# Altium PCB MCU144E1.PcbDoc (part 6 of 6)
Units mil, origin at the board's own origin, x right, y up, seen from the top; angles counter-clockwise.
Board outline 2755.9 x 2276.49 mil, 10 copper layers (Top Layer, L02_GND1, L03_SIG1, L04_GND2, L05_SIG2, L06_PWR, L07_GND3, L08_SIG3, L09_GND4, Bottom Layer), stack 60.4 mil thick; 257 components, 312 nets, 1297 pads, 831 vias.

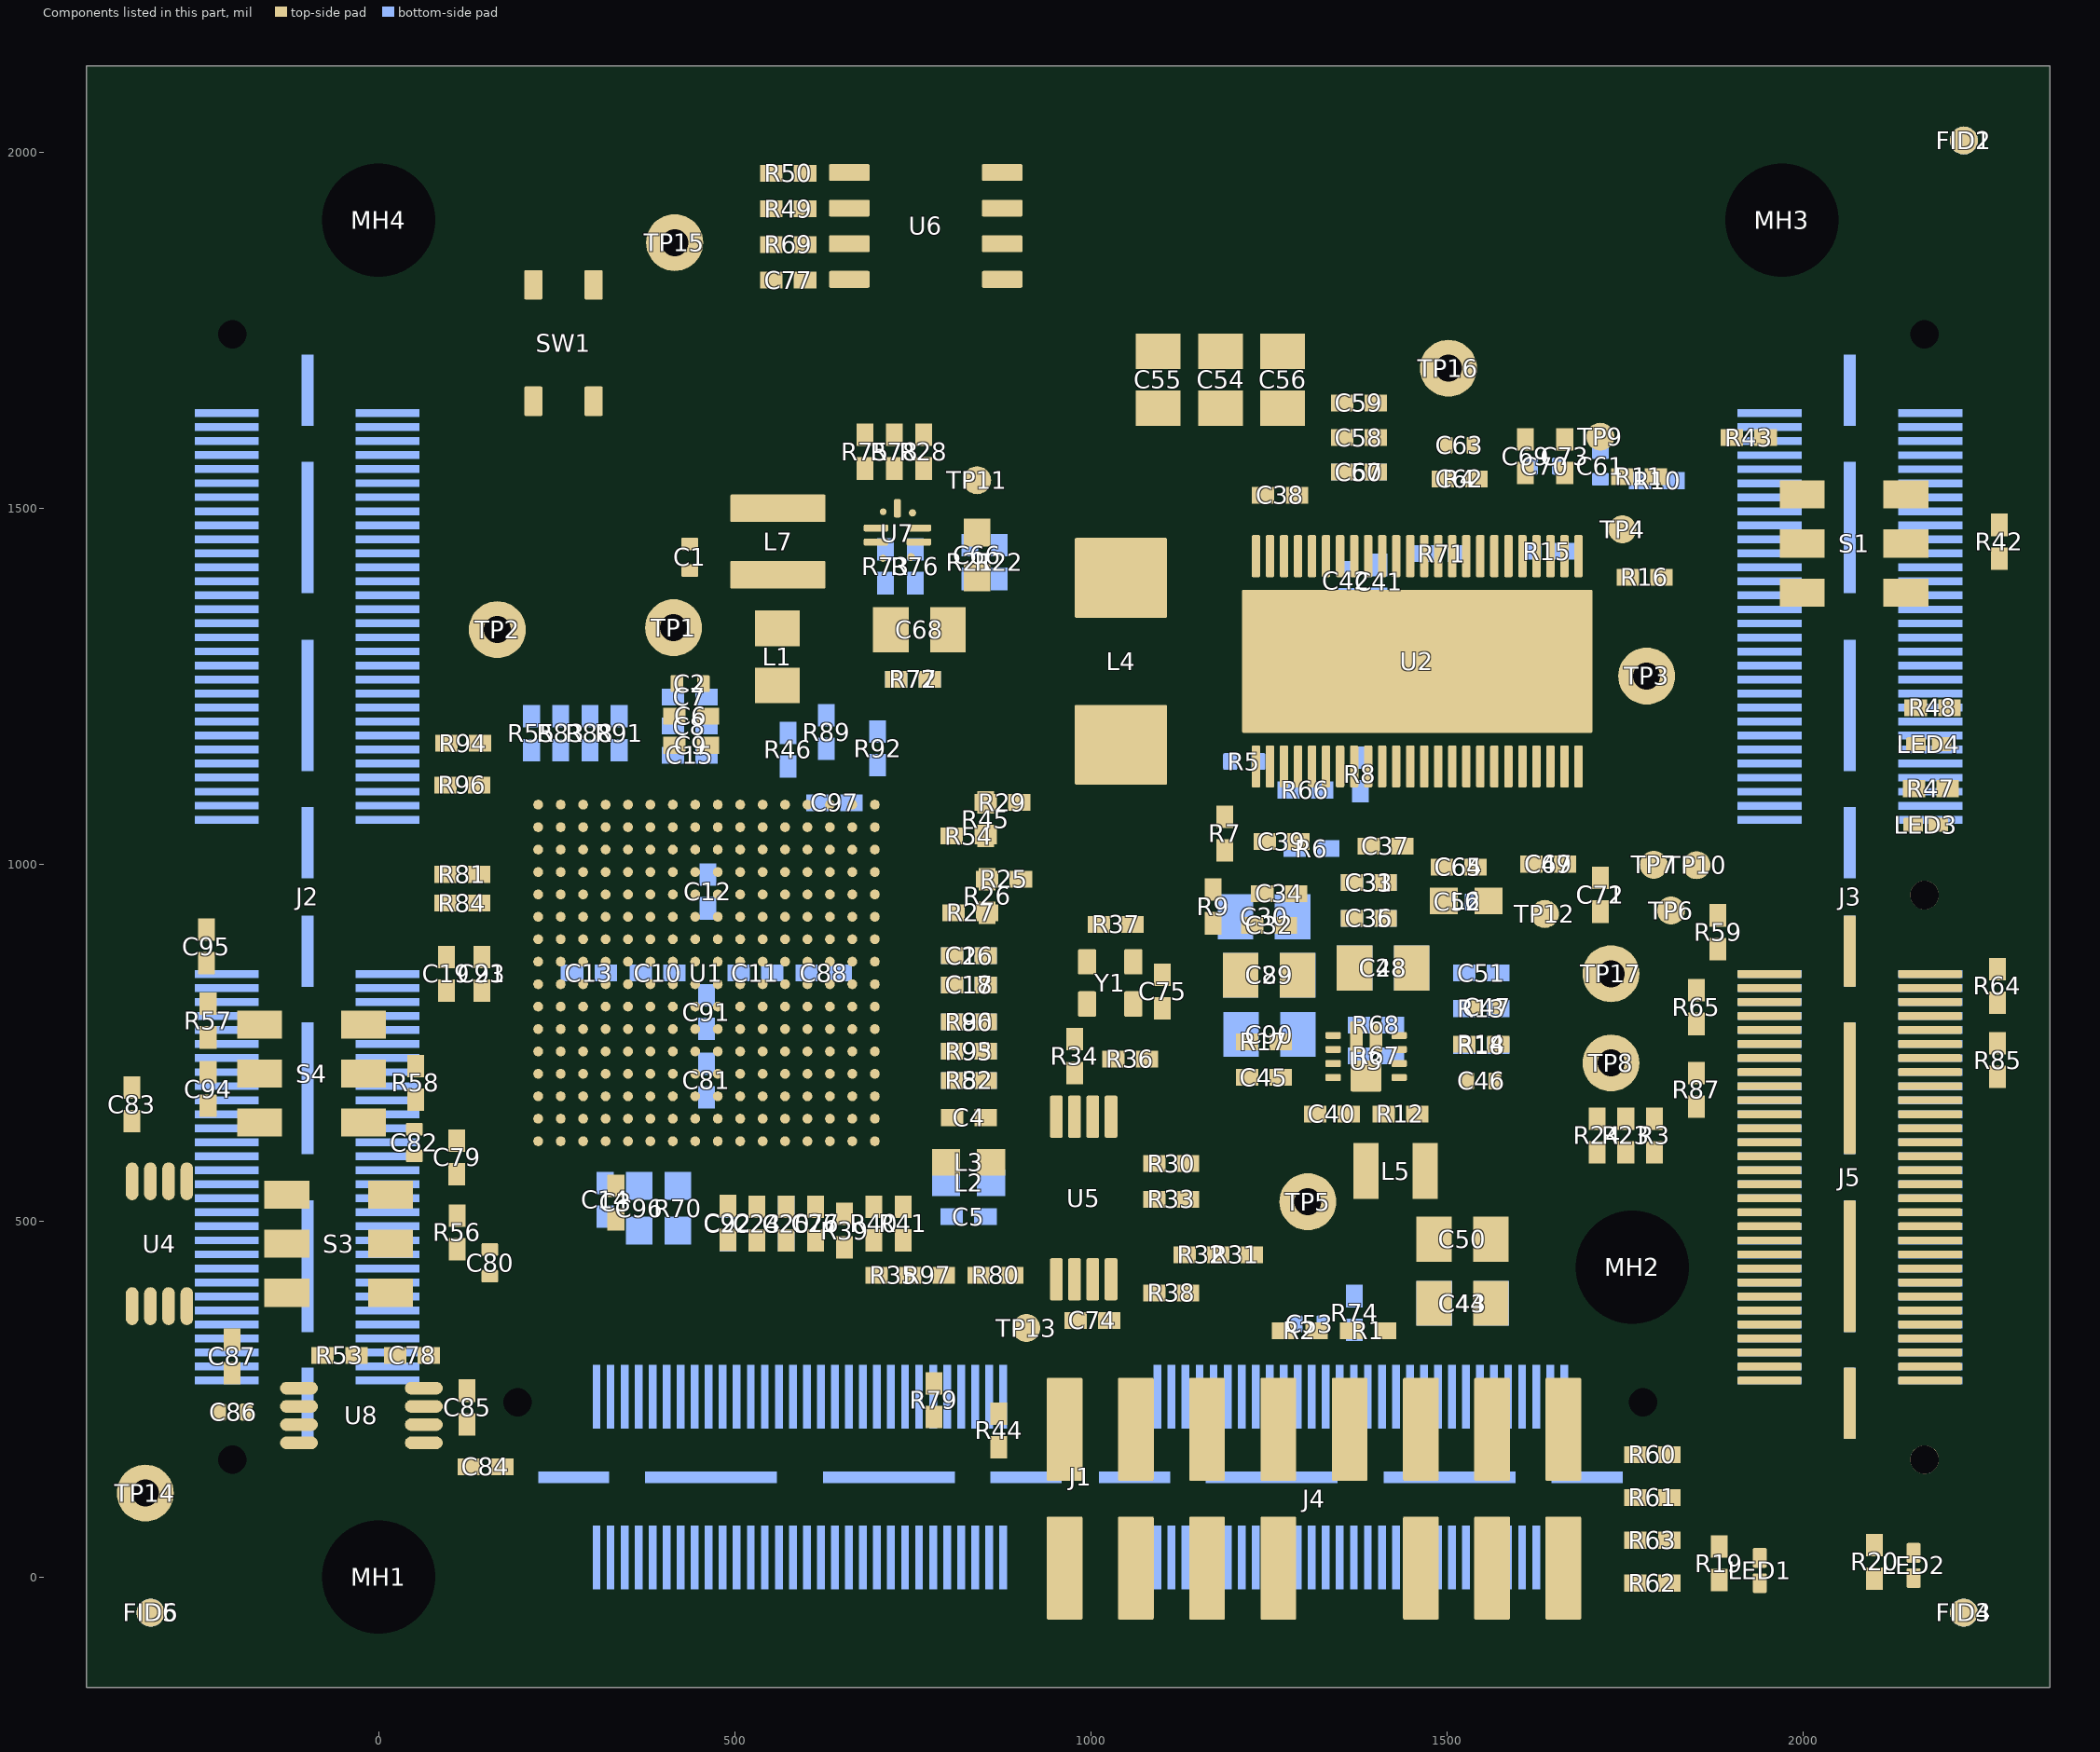
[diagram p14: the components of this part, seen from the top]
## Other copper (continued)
L08_SIG3:
  pour cut-out: 1221.72,1187.13 cw(c1221.72,1199.13) 1209.72,1199.13 cw(c1221.72,1199.13) 1221.72,1211.13 cw(c1221.72,1199.13) 1233.72,1199.13 cw(c1221.72,1199.13)
  pour cut-out: 1646.92,1187.13 cw(c1646.92,1199.13) 1634.92,1199.13 cw(c1646.92,1199.13) 1646.92,1211.13 cw(c1646.92,1199.13) 1658.92,1199.13 cw(c1646.92,1199.13)
  pour cut-out: 1694.16,1187.13 cw(c1694.16,1199.13) 1682.16,1199.13 cw(c1694.16,1199.13) 1694.16,1211.13 cw(c1694.16,1199.13) 1706.16,1199.13 cw(c1694.16,1199.13)
  pour cut-out: 1694.16,1230.43 cw(c1694.16,1242.43) 1682.16,1242.43 cw(c1694.16,1242.43) 1694.16,1254.43 cw(c1694.16,1242.43) 1706.16,1242.43 cw(c1694.16,1242.43)
  pour cut-out: 1694.16,1317.05 cw(c1694.16,1329.05) 1682.16,1329.05 cw(c1694.16,1329.05) 1694.16,1341.05 cw(c1694.16,1329.05) 1706.16,1329.05 cw(c1694.16,1329.05)
  pour cut-out: 1694.16,1360.35 cw(c1694.16,1372.35) 1682.16,1372.35 cw(c1694.16,1372.35) 1694.16,1384.35 cw(c1694.16,1372.35) 1706.16,1372.35 cw(c1694.16,1372.35)
  pour cut-out: 1646.92,1360.35 cw(c1646.92,1372.35) 1634.92,1372.35 cw(c1646.92,1372.35) 1646.92,1384.35 cw(c1646.92,1372.35) 1658.92,1372.35 cw(c1646.92,1372.35)
  pour cut-out: 1599.67,1360.35 cw(c1599.67,1372.35) 1587.67,1372.35 cw(c1599.67,1372.35) 1599.67,1384.35 cw(c1599.67,1372.35) 1611.67,1372.35 cw(c1599.67,1372.35)
  pour cut-out: 1552.43,1360.35 cw(c1552.43,1372.35) 1540.43,1372.35 cw(c1552.43,1372.35) 1552.43,1384.35 cw(c1552.43,1372.35) 1564.43,1372.35 cw(c1552.43,1372.35)
  pour cut-out: 1505.18,1360.35 cw(c1505.18,1372.35) 1493.18,1372.35 cw(c1505.18,1372.35) 1505.18,1384.35 cw(c1505.18,1372.35) 1517.18,1372.35 cw(c1505.18,1372.35)
  pour cut-out: 1457.94,1360.35 cw(c1457.94,1372.35) 1445.94,1372.35 cw(c1457.94,1372.35) 1457.94,1384.35 cw(c1457.94,1372.35) 1469.94,1372.35 cw(c1457.94,1372.35)
  pour cut-out: 1316.21,1360.35 cw(c1316.21,1372.35) 1304.21,1372.35 cw(c1316.21,1372.35) 1316.21,1384.35 cw(c1316.21,1372.35) 1328.21,1372.35 cw(c1316.21,1372.35)
  pour cut-out: 1268.96,1360.35 cw(c1268.96,1372.35) 1256.96,1372.35 cw(c1268.96,1372.35) 1268.96,1384.35 cw(c1268.96,1372.35) 1280.96,1372.35 cw(c1268.96,1372.35)
  pour cut-out: 1221.72,1230.43 cw(c1221.72,1242.43) 1209.72,1242.43 cw(c1221.72,1242.43) 1221.72,1254.43 cw(c1221.72,1242.43) 1233.72,1242.43 cw(c1221.72,1242.43)
  pour cut-out: 1221.72,1273.74 cw(c1221.72,1285.74) 1209.72,1285.74 cw(c1221.72,1285.74) 1221.72,1297.74 cw(c1221.72,1285.74) 1233.72,1285.74 cw(c1221.72,1285.74)
  pour cut-out: 1221.72,1317.05 cw(c1221.72,1329.05) 1209.72,1329.05 cw(c1221.72,1329.05) 1221.72,1341.05 cw(c1221.72,1329.05) 1233.72,1329.05 cw(c1221.72,1329.05)
  pour cut-out: 1221.72,1360.35 cw(c1221.72,1372.35) 1209.72,1372.35 cw(c1221.72,1372.35) 1221.72,1384.35 cw(c1221.72,1372.35) 1233.72,1372.35 cw(c1221.72,1372.35)
  pour cut-out: 951.38,584.38 cw(c951.38,596.38) 939.38,596.38 cw(c951.38,596.38) 951.38,608.38 cw(c951.38,596.38) 963.38,596.38 cw(c951.38,596.38)
  pour cut-out: 180.44,1638.94 cw(c180.44,1650.94) 168.44,1650.94 cw(c180.44,1650.94) 180.44,1662.94 cw(c180.44,1650.94) 192.44,1650.94 cw(c180.44,1650.94)
  pour cut-out: 509.25,1810 cw(c509.25,1822) 497.25,1822 cw(c509.25,1822) 509.25,1834 cw(c509.25,1822) 521.25,1822 cw(c509.25,1822)
  pour cut-out: 509.25,1860 cw(c509.25,1872) 497.25,1872 cw(c509.25,1872) 509.25,1884 cw(c509.25,1872) 521.25,1872 cw(c509.25,1872)
  pour cut-out: 936.95,1860 cw(c936.95,1872) 924.95,1872 cw(c936.95,1872) 936.95,1884 cw(c936.95,1872) 948.95,1872 cw(c936.95,1872)
  pour cut-out: 724,1623.21 cw(c724,1635.21) 712,1635.21 cw(c724,1635.21) 724,1647.21 cw(c724,1635.21) 736,1635.21 cw(c724,1635.21)
  pour cut-out: 765,1623.21 cw(c765,1635.21) 753,1635.21 cw(c765,1635.21) 765,1647.21 cw(c765,1635.21) 777,1635.21 cw(c765,1635.21)
  pour cut-out: 1620.79,1625.88 cw(c1620.79,1637.88) 1608.79,1637.88 cw(c1620.79,1637.88) 1620.79,1649.88 cw(c1620.79,1637.88) 1632.79,1637.88 cw(c1620.79,1637.88)
  pour cut-out: 1571.68,1624.97 cw(c1571.68,1636.97) 1559.68,1636.97 cw(c1571.68,1636.97) 1571.68,1648.97 cw(c1571.68,1636.97) 1583.68,1636.97 cw(c1571.68,1636.97)
  pour cut-out: 1521.26,1624.97 cw(c1521.26,1636.97) 1509.26,1636.97 cw(c1521.26,1636.97) 1521.26,1648.97 cw(c1521.26,1636.97) 1533.26,1636.97 cw(c1521.26,1636.97)
  pour cut-out: 1435.68,1625.82 cw(c1435.68,1637.82) 1423.68,1637.82 cw(c1435.68,1637.82) 1435.68,1649.82 cw(c1435.68,1637.82) 1447.68,1637.82 cw(c1435.68,1637.82)
  pour cut-out: 1936.77,52.55 cw(c1936.77,64.55) 1924.77,64.55 cw(c1936.77,64.55) 1936.77,76.55 cw(c1936.77,64.55) 1948.77,64.55 cw(c1936.77,64.55)
  pour cut-out: 2065,318.61 cw(c2065,330.61) 2053,330.61 cw(c2065,330.61) 2065,342.61 cw(c2065,330.61) 2077,330.61 cw(c2065,330.61)
  pour cut-out: 1169.18,518.38 cw(c1169.18,530.38) 1157.18,530.38 cw(c1169.18,530.38) 1169.18,542.38 cw(c1169.18,530.38) 1181.18,530.38 cw(c1169.18,530.38)
  pour cut-out: 1166,785.5 cw(c1166,797.5) 1154,797.5 cw(c1166,797.5) 1166,809.5 cw(c1166,797.5) 1178,797.5 cw(c1166,797.5)
  pour cut-out: 1593.48,684.52 cw(c1593.48,696.52) 1581.48,696.52 cw(c1593.48,696.52) 1593.48,708.52 cw(c1593.48,696.52) 1605.48,696.52 cw(c1593.48,696.52)
  pour cut-out: 2065,569.43 cw(c2065,581.43) 2053,581.43 cw(c2065,581.43) 2065,593.43 cw(c2065,581.43) 2077,581.43 cw(c2065,581.43)
  pour cut-out: 2065,318.61 cw(c2065,330.61) 2053,330.61 cw(c2065,330.61) 2065,342.61 cw(c2065,330.61) 2077,330.61 cw(c2065,330.61)
  pour cut-out: 2154.81,51.4 cw(c2154.81,63.4) 2142.81,63.4 cw(c2154.81,63.4) 2154.81,75.4 cw(c2154.81,63.4) 2166.81,63.4 cw(c2154.81,63.4)
  pour cut-out: 1506.84,70.74 cw(c1506.84,82.74) 1494.84,82.74 cw(c1506.84,82.74) 1506.84,94.74 cw(c1506.84,82.74) 1518.84,82.74 cw(c1506.84,82.74)
  pour cut-out: 1315,128 cw(c1315,140) 1303,140 cw(c1315,140) 1315,152 cw(c1315,140) 1327,140 cw(c1315,140)
  pour cut-out: 1115,128 cw(c1115,140) 1103,140 cw(c1115,140) 1115,152 cw(c1115,140) 1127,140 cw(c1115,140)
  pour cut-out: 1025.56,315.1 cw(c1025.56,327.1) 1013.56,327.1 cw(c1025.56,327.1) 1025.56,339.1 cw(c1025.56,327.1) 1037.56,327.1 cw(c1025.56,327.1)
  pour cut-out: 815,151 cw(c815,163) 803,163 cw(c815,163) 815,175 cw(c815,163) 827,163 cw(c815,163)
  pour cut-out: 700.81,308.3 cw(c700.81,320.3) 688.81,320.3 cw(c700.81,320.3) 700.81,332.3 cw(c700.81,320.3) 712.81,320.3 cw(c700.81,320.3)
  pour cut-out: -339.37,441.54 cw(c-339.37,453.54) -351.37,453.54 cw(c-339.37,453.54) -339.37,465.54 cw(c-339.37,453.54) -327.37,453.54 cw(c-339.37,453.54)
  pour cut-out: -337.61,501.04 cw(c-337.61,513.04) -349.61,513.04 cw(c-337.61,513.04) -337.61,525.04 cw(c-337.61,513.04) -325.61,513.04 cw(c-337.61,513.04)
  pour cut-out: 99.44,272.6 cw(c99.44,284.6) 87.44,284.6 cw(c99.44,284.6) 99.44,296.6 cw(c99.44,284.6) 111.44,284.6 cw(c99.44,284.6)
  pour cut-out: 8.92,228.11 cw(c8.92,240.11) -3.08,240.11 cw(c8.92,240.11) 8.92,252.11 cw(c8.92,240.11) 20.92,240.11 cw(c8.92,240.11)
  pour cut-out: -76.47,519.83 cw(c-76.47,531.83) -88.47,531.83 cw(c-76.47,531.83) -76.47,543.83 cw(c-76.47,531.83) -64.47,531.83 cw(c-76.47,531.83)
  pour cut-out: -77.37,425.84 cw(c-77.37,437.84) -89.37,437.84 cw(c-77.37,437.84) -77.37,449.84 cw(c-77.37,437.84) -65.37,437.84 cw(c-77.37,437.84)
  pour cut-out: 333.39,458.53 cw(c333.39,470.53) 321.39,470.53 cw(c333.39,470.53) 333.39,482.53 cw(c333.39,470.53) 345.39,470.53 cw(c333.39,470.53)
  pour cut-out: 1446.33,913 cw(c1446.33,925) 1434.33,925 cw(c1446.33,925) 1446.33,937 cw(c1446.33,925) 1458.33,925 cw(c1446.33,925)
  pour cut-out: 1446.33,963 cw(c1446.33,975) 1434.33,975 cw(c1446.33,975) 1446.33,987 cw(c1446.33,975) 1458.33,975 cw(c1446.33,975)
  pour cut-out: 1166,858 cw(c1166,870) 1154,870 cw(c1166,870) 1166,882 cw(c1166,870) 1178,870 cw(c1166,870)
  pour cut-out: 887.7,860.1 cw(c887.7,872.1) 875.7,872.1 cw(c887.7,872.1) 887.7,884.1 cw(c887.7,872.1) 899.7,872.1 cw(c887.7,872.1)
  pour cut-out: 680.73,962.2 cw(c680.73,974.2) 668.73,974.2 cw(c680.73,974.2) 680.73,986.2 cw(c680.73,974.2) 692.73,974.2 cw(c680.73,974.2)
  pour cut-out: 712.23,1088.18 cw(c712.23,1100.18) 700.23,1100.18 cw(c712.23,1100.18) 712.23,1112.18 cw(c712.23,1100.18) 724.23,1100.18 cw(c712.23,1100.18)
  pour cut-out: 428.76,773.22 cw(c428.76,785.22) 416.76,785.22 cw(c428.76,785.22) 428.76,797.22 cw(c428.76,785.22) 440.76,785.22 cw(c428.76,785.22)
  pour cut-out: 428.76,804.72 cw(c428.76,816.72) 416.76,816.72 cw(c428.76,816.72) 428.76,828.72 cw(c428.76,816.72) 440.76,816.72 cw(c428.76,816.72)
  pour cut-out: 428.76,867.71 cw(c428.76,879.71) 416.76,879.71 cw(c428.76,879.71) 428.76,891.71 cw(c428.76,879.71) 440.76,879.71 cw(c428.76,879.71)
  pour cut-out: 397.27,867.71 cw(c397.27,879.71) 385.27,879.71 cw(c397.27,879.71) 397.27,891.71 cw(c397.27,879.71) 409.27,879.71 cw(c397.27,879.71)
  pour cut-out: 208.29,1088.18 cw(c208.29,1100.18) 196.29,1100.18 cw(c208.29,1100.18) 208.29,1112.18 cw(c208.29,1100.18) 220.29,1100.18 cw(c208.29,1100.18)
  pour cut-out: 1075.84,629.06 1075.84,604.16 1149.62,530.38 1169.18,530.38 1188.8,550 1200,550 1100,650
  text ".Layer_Name" at -94.71,-2471.24 h60
L09_GND4:
  text ".Layer_Name" at -77.19,-2506.29 h60
L05_SIG2:
  pour cut-out: 1410.7,1273.74 cw(c1410.7,1285.74) 1398.7,1285.74 cw(c1410.7,1285.74) 1410.7,1297.74 cw(c1410.7,1285.74) 1422.7,1285.74 cw(c1410.7,1285.74)
  pour cut-out: 1457.94,1230.43 cw(c1457.94,1242.43) 1445.94,1242.43 cw(c1457.94,1242.43) 1457.94,1254.43 cw(c1457.94,1242.43) 1469.94,1242.43 cw(c1457.94,1242.43)
  pour cut-out: 1410.7,1187.13 cw(c1410.7,1199.13) 1398.7,1199.13 cw(c1410.7,1199.13) 1410.7,1211.13 cw(c1410.7,1199.13) 1422.7,1199.13 cw(c1410.7,1199.13)
  pour cut-out: 1363.45,1230.43 cw(c1363.45,1242.43) 1351.45,1242.43 cw(c1363.45,1242.43) 1363.45,1254.43 cw(c1363.45,1242.43) 1375.45,1242.43 cw(c1363.45,1242.43)
  pour cut-out: 1457.94,1187.13 cw(c1457.94,1199.13) 1445.94,1199.13 cw(c1457.94,1199.13) 1457.94,1211.13 cw(c1457.94,1199.13) 1469.94,1199.13 cw(c1457.94,1199.13)
  pour cut-out: 1410.7,1230.43 cw(c1410.7,1242.43) 1398.7,1242.43 cw(c1410.7,1242.43) 1410.7,1254.43 cw(c1410.7,1242.43) 1422.7,1242.43 cw(c1410.7,1242.43)
  pour cut-out: 1363.45,1273.74 cw(c1363.45,1285.74) 1351.45,1285.74 cw(c1363.45,1285.74) 1363.45,1297.74 cw(c1363.45,1285.74) 1375.45,1285.74 cw(c1363.45,1285.74)
  pour cut-out: 1316.21,1317.05 cw(c1316.21,1329.05) 1304.21,1329.05 cw(c1316.21,1329.05) 1316.21,1341.05 cw(c1316.21,1329.05) 1328.21,1329.05 cw(c1316.21,1329.05)
  pour cut-out: 1363.45,1317.05 cw(c1363.45,1329.05) 1351.45,1329.05 cw(c1363.45,1329.05) 1363.45,1341.05 cw(c1363.45,1329.05) 1375.45,1329.05 cw(c1363.45,1329.05)
  pour cut-out: 1316.21,1360.35 cw(c1316.21,1372.35) 1304.21,1372.35 cw(c1316.21,1372.35) 1316.21,1384.35 cw(c1316.21,1372.35) 1328.21,1372.35 cw(c1316.21,1372.35)
  pour cut-out: 1268.96,1273.74 cw(c1268.96,1285.74) 1256.96,1285.74 cw(c1268.96,1285.74) 1268.96,1297.74 cw(c1268.96,1285.74) 1280.96,1285.74 cw(c1268.96,1285.74)
  pour cut-out: 1268.96,1360.35 cw(c1268.96,1372.35) 1256.96,1372.35 cw(c1268.96,1372.35) 1268.96,1384.35 cw(c1268.96,1372.35) 1280.96,1372.35 cw(c1268.96,1372.35)
  pour cut-out: 1268.96,1317.05 cw(c1268.96,1329.05) 1256.96,1329.05 cw(c1268.96,1329.05) 1268.96,1341.05 cw(c1268.96,1329.05) 1280.96,1329.05 cw(c1268.96,1329.05)
  pour cut-out: 1221.72,1187.13 cw(c1221.72,1199.13) 1209.72,1199.13 cw(c1221.72,1199.13) 1221.72,1211.13 cw(c1221.72,1199.13) 1233.72,1199.13 cw(c1221.72,1199.13)
  pour cut-out: 1221.72,1230.43 cw(c1221.72,1242.43) 1209.72,1242.43 cw(c1221.72,1242.43) 1221.72,1254.43 cw(c1221.72,1242.43) 1233.72,1242.43 cw(c1221.72,1242.43)
  pour cut-out: 1166,785.5 cw(c1166,797.5) 1154,797.5 cw(c1166,797.5) 1166,809.5 cw(c1166,797.5) 1178,797.5 cw(c1166,797.5)
  pour cut-out: 1011.15,926.85 cw(c1011.15,938.85) 999.15,938.85 cw(c1011.15,938.85) 1011.15,950.85 cw(c1011.15,938.85) 1023.15,938.85 cw(c1011.15,938.85)
  pour cut-out: 1534.05,1008.95 cw(c1534.05,1020.95) 1522.05,1020.95 cw(c1534.05,1020.95) 1534.05,1032.95 cw(c1534.05,1020.95) 1546.05,1020.95 cw(c1534.05,1020.95)
  pour cut-out: 1435.59,1659.08 cw(c1435.59,1671.08) 1423.59,1671.08 cw(c1435.59,1671.08) 1435.59,1683.08 cw(c1435.59,1671.08) 1447.59,1671.08 cw(c1435.59,1671.08)
  pour cut-out: 1620.79,1625.88 cw(c1620.79,1637.88) 1608.79,1637.88 cw(c1620.79,1637.88) 1620.79,1649.88 cw(c1620.79,1637.88) 1632.79,1637.88 cw(c1620.79,1637.88)
  pour cut-out: 1571.68,1624.97 cw(c1571.68,1636.97) 1559.68,1636.97 cw(c1571.68,1636.97) 1571.68,1648.97 cw(c1571.68,1636.97) 1583.68,1636.97 cw(c1571.68,1636.97)
  pour cut-out: 1521.26,1624.97 cw(c1521.26,1636.97) 1509.26,1636.97 cw(c1521.26,1636.97) 1521.26,1648.97 cw(c1521.26,1636.97) 1533.26,1636.97 cw(c1521.26,1636.97)
  pour cut-out: 1435.68,1625.82 cw(c1435.68,1637.82) 1423.68,1637.82 cw(c1435.68,1637.82) 1435.68,1649.82 cw(c1435.68,1637.82) 1447.68,1637.82 cw(c1435.68,1637.82)
  pour cut-out: 778.23,1383.49 cw(c778.23,1395.49) 766.23,1395.49 cw(c778.23,1395.49) 778.23,1407.49 cw(c778.23,1395.49) 790.23,1395.49 cw(c778.23,1395.49)
  pour cut-out: 712.23,1088.18 cw(c712.23,1100.18) 700.23,1100.18 cw(c712.23,1100.18) 712.23,1112.18 cw(c712.23,1100.18) 724.23,1100.18 cw(c712.23,1100.18)
  pour cut-out: 554.75,867.71 cw(c554.75,879.71) 542.75,879.71 cw(c554.75,879.71) 554.75,891.71 cw(c554.75,879.71) 566.75,879.71 cw(c554.75,879.71)
  text ".Layer_Name" at -129.75,-2497.53 h60
L06_PWR:
  text ".Layer_Name" at -94.71,-2506.29 h60
Bottom Layer:
  region net GND: 371.29,1276.71 371.29,1265.71 399.55,1237.45 399.55,1155.7 427.44,1155.7 427.44,1248.36 407.4,1268.4 391.66,1268.4 380.35,1279.71 374.29,1279.71
  region net VDDIO_3V3: 423.53,759.93 438.91,759.93 448.45,769.47 448.45,785.22 472.07,785.22 472.07,769.47 482.77,758.77 528.64,758.77 532.13,755.28 532.13,736.44 537.57,731 559,731 565,725 565,716 562,713 519,713 514.36,717.64 514.36,728.47 503.12,739.71 475.32,739.71 472.07,736.46 472.07,704.97 448.45,704.97 448.45,736.46 438.81,746.1 423.6,746.1
  region net GND: 429.47,775.44 433.26,779.22 433.26,789.71 444.51,800.97 475.98,800.97 487.51,789.43 487.51,784.38 496.46,775.44 557.24,775.44 566.07,784.27 565.03,785.31 565.03,822.66 562.22,825.47 523.72,825.47 520.88,828.31 520.88,860.02 531.44,870.58 556.37,870.58 557.85,872.06 557.85,939.59 548.55,948.89 403.54,948.89 399.63,945.03 399.63,836.4 409.55,836.4 417.53,828.42 417.53,798.14 415.01,795.62 393.88,795.62 388.2,789.94 388.2,748.63 392.93,743.9 403.97,743.9 409.02,748.95 409.02,771.34 413.11,775.44
  region net VDD_1V25: 501.62,983.93 501.62,983.75 503.04,982.32 503.04,966.75 499.74,963.45 420.77,963.45 417.48,966.75 417.48,982.32 421.84,986.69 432.7,986.69 444.51,998.5 444.51,1256.39 413.9,1287 395.12,1287 364.42,1317.7 364.42,1348.83 388.36,1372.77 432.23,1372.77 510,1295 510,1144.96 478.35,1113.31 478.35,996.16 487.82,986.69 498.85,986.69
  region net GND: 1528.65,1030 1524.79,1026.14 1524.79,930.21 1530,925 1555,925 1560,930 1560,1025 1555,1030
  region net GND: 1455,1005 1450,1010 1405,1010 1397.87,1002.87 1397.87,913.63 1425,886.5 1425,823.5 1430.06,818.44 1522.32,818.44 1540,836.12 1540,859.74 1519.74,880 1481.5,880 1455,906.5
  region net GND: 1154.51,915 1145,905.49 1145,715 1155,705 1222,705 1236.5,719.5 1236.5,963.5 1230,970 1166.01,970 1154.51,958.5
  region net 5V0_LDO2: 1508.25,1008.81 1478.36,1008.81 1475,1005.45 1475,908.83 1487.47,896.36 1506.36,896.36 1508.25,898.25
  region net 5V0_IN: 1240,520 1310,450 1360,450 1419.45,390.55 1419.45,367.62 1481.57,305.5 1481.57,208.19 1512.25,208.19 1512.25,534.25 1531.48,553.48 1667.22,553.48 1690.18,576.44 1792.08,576.44 1797.51,571 1825.72,571 1831.62,576.9 1831.62,590.38 1822,600 1769,600 1747,622 1499,622 1446.35,674.65 1348.35,674.65 1259.94,674.65 1255.38,670.1 1255.38,640.38 1240,625
  region net 3V3_OUT: 836.04,656.39 836.51,656.86 894.58,656.86 905,646.44 905,500 895,490 840.21,490 836.04,494.17
  region net +12V0: 1318.73,712.95 1322.89,717.11 1322.89,792.81 1332.26,802.18 1353.86,802.18 1359.23,796.81 1391.81,796.81 1395,800 1395,886.5 1382.13,899.37 1382.13,1017.87 1365,1035 1364.46,1034.46 1317.44,1034.46 1313.92,1030.94 1313.92,983.92 1300,970 1265,970 1257.17,962.17 1257.17,719.73 1263.96,712.95
  text ".Layer_Name" at -234.88,-2497.53 h60

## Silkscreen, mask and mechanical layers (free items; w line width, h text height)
Top Overlay:
  region: -223.23,1690 -223.23,1495 -125,1495 -125,1690
  lines w6: -162.58,360.87 -162.58,198.61 -162.58,191.75 -152.4,181.57 ; -95.19,825.63 -95.19,945 -95.19,1311.08 -35.63,1370.64 -35.63,1356.89 -49.56,1370.81 -35.46,1370.81 ; -25.03,825.28 -24.69,825.63 ; 150.03,582 142.03,590 ; 150.03,598 142.03,590 ; 176.2,15.49 176.2,43.8 190,30 176.2,16.2 ; 176.2,29.64 114.07,29.64 24,119.71 -152.41,119.71 -152.41,181.56 ; 220,545 190,545 185,550 185,575 170,590 142.03,590 ; 790,1505 805,1505 805,1575 ; 1101,500 1183,500 1183,570 ; 1325,980 1325,899 ; 1333,907 1325,899 ; 1334,907 1317,907 1325,899 ; 1429.03,1692.22 1429.03,1797.22 ; 1450,990 1450,915 1450,908.53 1489.47,908.53 1494,904 ; 1710.51,-67.52 1741.19,-67.52 1742.81,-67.52 1754.95,-79.66 ; 1719,1178 1719,1097 ; -152.41,181.56 -152.4,181.57 ; -152.4,181.57 -152.4,181.57 ; 805,1575 815,1565 795,1565 805,1575 ; 1429.03,1797.22 1439.03,1787.22 1419.03,1787.22 1429.03,1797.22 ; 1719,1097 1727,1105 1728,1105 1711,1105 1719,1097 ; 91.03,1430.17 263.45,1430.17 263.45,1566.23 91.03,1566.23 91.03,1430.17 ; 371.95,7.17 371.95,143.24 544.37,143.24 544.37,7.17 371.95,7.17
  lines w7: 385,380 385,413.1 391.9,420 655,420 ; 394.37,422.47 394.37,474.37 420,500 445,500 ; 430,485 445,500 ; 430,515 445,500 ; 827.53,1108.08 831.4,1111.96 ; 829.92,1000.44 833.8,1004.32 ; 872.4,1015.96 875.85,1019.4 ; 874.8,908.32 878.67,912.2 ; 1755,915 1755,1030 1760,1035
  text "XRSn" at 350,1985 h55
  text "F29H85X-SOM-EVM" at 985,1835 h90
  text "3V3" at 1465,1750 h55
  text "MCU RESET" at 375,1630 h45
  text "3V0" at -10.05,1623.88 h55
  text "Ext" at 215,1585 h55
  text "VREF" at -20,1580 h55
  text "6V0" at 880,1570 h55
  text "BOOT" at 2010.53,1569.57 h55
  text "0" at 2185.68,1556.86 h25
  text "-" at -165,1450 h60 r90
  text "Ext" at 15,1450 h55 r90
  text "CDE" at 365,1445 h55 r90
  text "VREF" at 64.69,1427.92 h55 r90
  text "VREFHI" at 320.71,1397.79 h55 r90
  text "Int" at 216.58,1376.42 h55
  text "J1.83" at -25,1375 h55
  text "GPIO72" at 2220,1375 h50 r90
  text "GPIO84" at 1955,1370 h50 r90
  text "1" at 2175,1320 h25
  text "3V3" at 40,1240 h55
  text "GND" at 1845,1225 h50
  text "GPIO9" at 1965,1210 h50
  text "GPIO23" at 1944.62,1085.55 h50
  text "*" at 1740,1071 h55
  text "'.PRJ_Number'.PCB_Rev" at -150,1010 h90 r90
  text "*" at 1312.08,968.52 h55
  text "5V0" at 1783.48,874.31 h45
  text "+12V" at 1570,529 h55
  text "5V0" at 1355,460 h55
  text "GND" at 1314.89,283.87 h50
  text "3V0" at 305,205 h55
  text "Ext" at 561.42,180.57 h55
  text "VREF" at 295,155 h55
  text "AB" at 650,45 h55 r90
  text "Ext" at 300,25 h55 r90
  text "VREF" at 350,5 h55 r90
  text "3V3" at 2190,5 h55
  text "VREFHI" at 605,-15 h55 r90
  text "J1.85" at 270,-55 h55
  text "Int" at 559.81,-68.41 h55
  text "5V0" at 1910,-90 h55
  text "GND" at 1770,-125 h55
  text "Emulation Connector" at 1080,-130 h55
  text ".Layer_Name" at -294.41,-2501.36 h60
Bottom Overlay:
  rectangle: 203.93,1979.18 892.37,2077.42
  lines w6: 1457.74,1009.33 1457.74,1089.33 ; 1480.74,1044.33 1480.74,1124.33 ; 1790,850 1835,850 ; 1457.74,1089.33 1447.74,1079.33 1467.74,1079.33 1457.74,1089.33 ; 1480.74,1124.33 1490.74,1114.33 1470.74,1114.33 1480.74,1124.33 ; 1835,850 1825,840 1825,860 1835,850
  lines w7: 300,1250 325,1250 345,1270 345,1300 ; 335,1260 345,1250 375,1250
  lines w10: 891.81,1979.18 891.81,2077.42 ; 1030.11,1977.13 1030.11,2077.27 203.93,2077.27 203.93,1977.27 1030.11,1977.27
  lines w20: 138.59,107.01 138.59,305.58 138.59,328.14 1237.29,328.14 ; 181.41,-88.7 1834.24,-88.7 1834.24,61.99 1833.97,61.99 1833.97,297.4 1812.1,297.4 ; 1419.76,326.27 1630.39,326.27
  text "SL#" at 1017.5,2000.12 h70
  text "1V2" at 460,1384 h55
  text "GND" at 1830,1325 h55
  text "5V0_OUT_CAN" at 1850,835 h55 r270
  text "12V0" at 1783.68,631.48 h55
  text "5V0" at 1339.43,580.87 h55
  text ".Layer_Name" at 382.44,-2503.77 h60
Top Solder:
  text ".Layer_Name" at -291.91,-2489.62 h60
Bottom Solder:
  text ".Layer_Name" at -393.77,-2489.7 h60
Drill Guide:
  text ".Layer_Name" at -323.89,-2500.75 h60
M1 Board Outline:
  the board outline again, w20
M2 Board Dimensions:
  text ".Layer_Name" at -335.67,-2480.71 h60
Top M5 Assembly Top/M6 Assembly Bottom:
  lines w10: -1192.39,-2572.42 5407.61,-2572.42 ; -1192.39,-2369.09 5409.61,-2369.09 ; -1192.39,-2165.76 -1192.39,-2775.76 2812.61,-2775.76 5409.61,-2775.76 5409.61,-2165.76 -1191.89,-2165.76 -1191.89,-2775.76 383.61,-2775.76 ; 1272.61,-2775.76 1272.61,-2165.76 ; 2539.61,-2369.09 2539.61,-2165.76 ; 3379.61,-2369.09 3379.61,-2165.76 ; 4001.61,-2782.26 4001.61,-2579.42
  text "COMPONENTS MARKED 'DNP' SHOULD NOT BE POPULATED." at 253.11,-1960.76 h60
  text "ASSEMBLY VARIANT:" at 252.61,-2076.26 h60
  text ".VariantName" at 1288.61,-2076.26 h60
  text "PCB VIEWED FROM TOP SIDE" at -1128.89,-2297.92 h60
  text "BOARD #:" at 1347.61,-2297.92 h60
  text ".PRJ_Number" at 1893.11,-2297.92 h60
  text "REV:" at 2737.61,-2297.92 h60
  text ".PCB_Rev" at 3029.11,-2297.92 h60
  text "SVN REV:" at 3575.61,-2297.92 h60
  text ".VersionControl_RevNumber" at 4081.61,-2297.92 h60
  text "TID #:" at 1347.61,-2501.26 h60
  text ".TID" at 1893.11,-2501.26 h60
  text "PLOT NAME =" at -1128.89,-2706.59 h60
  text ".plot_File_Name" at -323.39,-2706.59 h60
  text "GENERATED    :" at 1349.61,-2706.59 h60
  text ".Print_Date" at 2219.11,-2706.59 h60
  text ".Print_Time" at 2948.11,-2706.59 h60
  text "TEXAS INSTRUMENTS" at 4212.61,-2706.59 h60
Bottom M5 Assembly Top/M6 Assembly Bottom:
  lines w10: -1192.39,-2369.09 5409.61,-2369.09 ; -1190.39,-2572.42 5409.61,-2572.42 ; 215.61,-2782.26 215.61,-2579.42 ; 837.61,-2369.09 837.61,-2165.76 ; 1677.61,-2369.09 1677.61,-2165.76 ; 2944.61,-2775.76 2944.61,-2165.76 ; 3833.61,-2775.76 5409.11,-2775.76 5409.11,-2165.76 -1192.39,-2165.76 -1192.39,-2775.76 1404.61,-2775.76 5409.61,-2775.76 5409.61,-2165.76
  text "COMPONENTS MARKED 'DNP' SHOULD NOT BE POPULATED." at 5202.11,-1959.76 h60
  text ".VariantName" at 4158.11,-2075.76 h60
  text "ASSEMBLY VARIANT:" at 5197.11,-2075.76 h60
  text ".VersionControl_RevNumber" at 135.61,-2297.92 h60
  text "SVN REV:" at 641.61,-2297.92 h60
  text ".PCB_Rev" at 1188.11,-2297.92 h60
  text "REV:" at 1479.61,-2297.92 h60
  text ".PRJ_Number" at 2324.11,-2297.92 h60
  text "BOARD #:" at 2869.61,-2297.92 h60
  text "PCB VIEWED FROM BOTTOM SIDE" at 5346.11,-2297.92 h60
  text ".TID" at 2324.11,-2501.26 h60
  text "TID #:" at 2869.61,-2501.26 h60
  text "TEXAS INSTRUMENTS" at 4.61,-2706.59 h60
  text ".Print_Time" at 1269.11,-2706.59 h60
  text ".Print_Date" at 1998.11,-2706.59 h60
  text "GENERATED    :" at 2867.61,-2706.59 h60
  text ".plot_File_Name" at 4540.61,-2706.59 h60
  text "PLOT NAME =" at 5346.11,-2706.59 h60
M10 Fab Notes:
  drawing of 244 lines, arcs and shapes, not listed
  text "DESIGN INFORMATION" at 11481.13,4853.92 h60
  text "3.5" at 11935,4725 h60
  text "MIN. TRACK WIDTH:" at 10836.57,4721.79 h60
  text "MIL" at 12087.57,4721.79 h60
  text "4" at 11880.75,4601.45 h60
  text "MIN. CLEARANCE:" at 10836.57,4597.66 h60
  text "MIL" at 12087.57,4597.66 h60
  text "MIN. VIA PAD SIZE:" at 10836.57,4473.54 h60
  text "18" at 11902.82,4473.54 h60
  text "MIL" at 12087.57,4473.54 h60
  text "SCALE : NTS" at 400,4397 h80
  text "0.05mm (2MIL)" at 11531.57,4343.64 h60
  text "MINIMUM ANNULAR RING" at 10507.34,4335.42 h60
  text "EXTERNAL" at 12239.57,4335.42 h60
  text "NOTES:" at -800.66,4246.41 h60
  text "PER" at 10707.34,4225.29 h60
  text "IPC-D-275 CLASS 2 LEVEL C" at 10927.34,4225.29 h60
  text "MIL, HOLES" at 12415.57,4124.81 h60
  text "+/-" at 12023.11,4116.23 h60
  text "+/-" at 12877.11,4116.23 h60
  text "REGISTRATION TOLERANCES:" at 10507.34,4115.16 h60
  text "METAL" at 11707.11,4115.16 h60
  text "5" at 12283.31,4115.16 h60
  text "3" at 13116.31,4115.16 h60
  text "MIL" at 13232.57,4115.16 h60
  text "1. BOARD SHALL MEET THE REQUIREMENTS OF UL-796E WITH FLAMMABILITY RATING OF MINIMUM 94V-0. UL LOGO," at -773.91,4100.59 h60
  text "IMPEDANCE TABLE :" at 6860,4095 h80
  text "HOLE SIZE TOLERANCE (UNLESS OTHERWISE SPECIFIED):" at 10507.34,4016.85 h60
  text "+/-" at 12877.11,4013.97 h60
  text "3" at 13116.31,4012.91 h60
  text "MIL" at 13232.57,4012.91 h60
  text "MANUFACTURER'S IDENTIFICATION AND DATE CODE LETTER SHALL BE RENDERED IN SILKSCREEN." at -667.18,4001.59 h60
  text "LAYER" at 6196.22,3921.58 h70
  text "TRACE WIDTH" at 6483.42,3920.73 h70
  text "SPACING" at 6968.42,3920.73 h70
  text "IMPEDANCE +/- 10%" at 7303.42,3920.73 h70
  text "REFERENCE LAYER" at 8028.42,3920.73 h70
  text "2. VENDOR MAY ADJUST SOLDERMASK WHEREVER SOLDERMASK PADS ARE THE SAME SIZE (1:1) AS PER THE MANUFACTURING CAPABILITIES" at -780.9,3875.81 h60
  text "MATERIAL:" at 10432.57,3875.26 h60
  text "AND ALL OTHER SOLDER MASK PADS SHALL NOT BE MODIFIED, PROVIDED NO ADJACENT COPPER IS EXPOSED AND NO CONFLICT IS PRODUCED" at -674.17,3776.81 h60
  text "-" at 7091,3750 h65
  text "FR-4 High Tg" at 11419.01,3746.74 h60
  text "LAYER-2 (GND LAYER)" at 7989.83,3744.77 h65
  text "5.66 MILS" at 6582.1,3739.75 h65
  text "50 OHM" at 7466.3,3740 h65
  text "X" at 11274.57,3738.75 h60
  text "TOP" at 6221,3735 h70
  text "FR-408" at 10853.57,3734.23 h60
  text "OTHER" at 12341.57,3734.23 h60
  text "WITH ANY STATED \"VIA TENTING/COVERING\" REQUIREMENTS." at -674.17,3683.52 h60
  text "62 MIL (1.6mm) +/-10%" at 11173.67,3591.2 h60
  text "X" at 11053.57,3588.75 h60
  text "THICKNESS:" at 10507.34,3582.98 h60
  text "OTHER" at 12458.57,3582.98 h60
  text "3. MANUFACTURER'S IDENTIFICATION,DATECODE LETTER SHALL BE SILKSCREENED ON SOLDER SIDE OF THE BOARD." at -777.22,3565.43 h60
  text "50 OHM" at 7463.76,3555.86 h65
  text "L3" at 6258.46,3555 h60
  text "-" at 7093.46,3555 h65
  text "4.5 MILS" at 6579.56,3550.86 h65
  text "LAYER-2 / LAYER-4" at 7987.29,3546.52 h65
  text "TOLERANCE:" at 10507.34,3444.67 h60
  text "ANSI IPC-6012 TYPE 3 CLASS 2" at 11533.58,3444.67 h60
  text "4. LAYER TO LAYER REGISTRATION SHALL BE WITHIN +/-5 MIL." at -777.22,3396.33 h60
  text "100 OHM" at 7463.76,3380.86 h65
  text "L3" at 6258.46,3380 h60
  text "3.5  MILS" at 6579.56,3375.86 h65
  text "6.7 MILS" at 6992.81,3375 h65
  text "LAYER-2 / LAYER-4" at 7987.29,3371.52 h65
  text "OTHER +/-" at 11533.57,3300.48 h60
  text "5. REFER IMPEDANCE TABLE FOR IMPEDANCE CONTROL TRACES ON LAYER 1, 3, 5 , 8 & 10." at -777.22,3230.46 h60
  text "-" at 7088.46,3205 h65
  text "50 OHM" at 7473.76,3205.42 h65
  text "LAYER-4/LAYER-6" at 7997.29,3194.23 h65
  text "L5" at 6258.46,3190 h60
  text "4.0 MILS" at 6579.56,3185 h65
  text "BOW & TWIST:" at 10507.34,3155.29 h60
  text "X" at 11355.57,3155.29 h60
  text "ANSI IPC-6012 TYPE 3 CLASS 2" at 11533.58,3155.29 h60
  text "6. ALL VIAS ARE TENTED ON BOTH SIDES UNLESS OTHERWISE SOLDER MASK OPENED IN GERBER." at -777.22,3070.31 h60
  text "-" at 7082.46,3030 h65
  text "50 OHM" at 7472.46,3025 h65
  text "LAYER-7/LAYER-9" at 8002.29,3024.29 h65
  text "L8" at 6258.46,3020 h60
  text "4.5 MILS" at 6579.56,3015 h65
  text "OTHER +/-" at 11533.57,3008.59 h60
  text "DRILLING:" at 10432.57,2877.97 h60
  text "L8" at 6258.46,2844.61 h60
  text "3.5  MILS" at 6579.56,2840.86 h65
  text "6.7 MILS" at 6992.81,2840.86 h65
  text "100 OHM" at 7467.46,2840.86 h65
  text "LAYER-7/LAYER-9" at 8002.29,2840.93 h65
  text "NC_DRILL FILES" at 12193.57,2772.78 h60
  text "REFERENCE:" at 10507.34,2768.85 h60
  text "X" at 11164.57,2768.75 h60
  text "AS SHOWN" at 11342.57,2768.85 h60
  text "X" at 12065.57,2768.85 h60
  text "LAYER-9(GND LAYER)" at 8002.29,2671.48 h65
  text "BOTTOM" at 6181.12,2659.94 h60
  text "5.66 MILS" at 6579.56,2660 h65
  text "-" at 7095,2660 h65
  text "50 OHM" at 7482.46,2660 h65
  text "OTHER" at 12491.57,2626.59 h60
  text "PTH COPPER THICKNESS:" at 10507.01,2623.07 h60
  text "X" at 11646.25,2623.07 h60
  text "20-30 um" at 11774.24,2623.07 h60
  text "LAYER-9(GND LAYER)" at 8002.29,2495.01 h65
  text "3.7 MILS" at 6579.56,2483.53 h65
  text "7.3 MILS" at 6992.81,2483.53 h65
  text "100 OHM" at 7472.46,2483.53 h65
  text "BOTTOM" at 6184.12,2483.47 h60
  text "BOARD FINISH:" at 10432.57,2475.47 h60
  text "SILKSCREEN:" at 10587.79,2365.34 h60
  text "X" at 11545.57,2365.34 h60
  text "TOP" at 11662.57,2365.34 h60
  text "X" at 12055.57,2365.34 h60
  text "BOTTOM" at 12173.57,2365.34 h60
  text "SILKSCREEN COLOR:" at 10587.79,2210.15 h60
  text "X" at 11544.57,2210.15 h60
  text "WHITE" at 11662.57,2210.15 h60
  text "OTHER" at 12173.57,2210.15 h60
  text "BLUE" at 12903.57,2076.71 h60
  text "GREEN" at 11793.57,2066.71 h60
  text "OTHER" at 12411.57,2066.71 h60
  text "X" at 12267,2064 h60
  text "SOLDER RESIST COLOR:" at 10587.79,2059.84 h60
  text "X" at 12265.97,1914.73 h60
  text "MATTE" at 11793.57,1912.45 h60
  text "SEMI-GLOSS" at 12411.11,1911.82 h60
  text "IMMERSION GOLD (ENIG)" at 11493.57,1739.68 h60
  text "ENEPIG" at 12831.11,1732.46 h60
  text "SURFACE FINISH:" at 10432.57,1731.46 h60
  text "X" at 11315.57,1731.46 h60
  text "IMM. TIN/SILVER OR EQUIV" at 10762.11,1594.15 h60
  text "OTHER" at 10783.57,1430.21 h60
  text "ARRAY/PANEL:" at 10432.57,1294.83 h60
  text "X" at 11320,1294 h60
  text "CUT AND TRIM PER M1 BOARD OUTLINE" at 11493.57,1286.61 h60
  text "N.C. ROUTE" at 11493.57,1150.64 h60
  text "V. SCORE" at 12359.57,1150.64 h60
  text "CERTIFICATION:" at 10432.57,1021.52 h60
  text "MATERIALS AND WORKMANSHIP FOR ALL PCBS" at 11157.57,1021.52 h60
  text "TO MEET OR EXCEED THE REQUIREMENTS OF:" at 11157.57,927.45 h60
  text "X" at 10795.08,798.82 h60
  text "ANSI IPC-A-600F CLASS ->" at 10923.07,798.82 h60
  text "X" at 12571.08,798.82 h60
  text "2" at 12681.07,798.82 h60
  text "1" at 12366.07,797.33 h60
  text "3" at 13035.07,797.33 h60
  text "X" at 11607.08,651.14 h60
  text "RoHS" at 11735.07,651.14 h60
  text "OTHER" at 12379.47,651.14 h60
  text "PER ORDER" at 12776.53,651.14 h60
  text "ALL BOARDS MUST MEET OR EXCEED UL94-V0 REQUIREMENTS." at 10460.11,497.31 h60
  text "PCB MUST BEAR THE UL94V-0 UL REGISTERED MATERIAL ID NUMBER" at 10460.11,381.25 h60
  text "ADDITIONAL REQUIREMENTS:" at 10432.57,211.82 h60
  text "REQUIRED" at 12214.57,90.36 h60
  text "BARE BOARD ELEC. TEST:" at 10447.34,87.51 h60
  text "NONE" at 11753.07,87.51 h60
  text "X" at 12689.11,87.74 h60
  text "PER ORDER" at 12806.57,87.51 h60
  text "OUTER LAYERS 6 MIL WIDE, 6 MIL SPACE / TRACES REQUIRE 100 OHM DIFFERENTIAL IMPEDANCE" at 10684.18,-214.19 h60
  text "INNER LAYERS 5 MIL WIDE, 7 MIL SPACE / TRACES REQUIRE 100 OHM DIFFERENTIAL IMPEDANCE" at 10654.18,-399.19 h60
  text "OUTER LAYERS 6.1 MIL WIDE, 6 MIL SPACE / TRACES REQUIRE 90 OHM DIFFERENTIAL IMPEDANCE" at 10666.5,-585.04 h60
  text ".Layer_Name" at -335.67,-2480.71 h60
M11 Gerber Information:
  lines w10: -1192.89,-2572.42 5407.11,-2572.42 ; -1192.89,-2369.09 5409.11,-2369.09 ; -1192.89,-2165.76 -1192.89,-2775.76 2812.11,-2775.76 5409.11,-2775.76 5409.11,-2165.76 -1192.39,-2165.76 -1192.39,-2775.76 383.11,-2775.76 ; 1272.11,-2775.76 1272.11,-2165.76 ; 2539.11,-2369.09 2539.11,-2165.76 ; 3379.11,-2369.09 3379.11,-2165.76 ; 4001.11,-2782.26 4001.11,-2579.42
  text "ALL ARTWORK VIEWED FROM TOP SIDE" at -1129.39,-2297.92 h60
  text "BOARD #:" at 1347.11,-2297.92 h60
  text ".PRJ_Number" at 1892.61,-2297.92 h60
  text "REV:" at 2737.11,-2297.92 h60
  text ".PCB_Rev" at 3028.61,-2297.92 h60
  text "SVN REV:" at 3575.11,-2297.92 h60
  text ".VersionControl_RevNumber" at 4081.11,-2297.92 h60
  text "LAYER NAME =" at -1129.39,-2500.75 h60
  text "TID #:" at 1347.11,-2501.26 h60
  text ".TID" at 1892.61,-2501.26 h60
  text "PLOT NAME =" at -1129.39,-2706.59 h60
  text ".plot_File_Name" at -323.89,-2706.59 h60
  text "GENERATED    :" at 1349.11,-2706.59 h60
  text ".Print_Date" at 2218.61,-2706.59 h60
  text ".Print_Time" at 2947.61,-2706.59 h60
  text "TEXAS INSTRUMENTS" at 4212.11,-2706.59 h60
M12 Stackup:
  drawing of 671 lines, arcs and shapes, not listed
  text "IMPEDANCE TABLE :" at 6860,4095 h80
  text "LAYER" at 6196.22,3921.58 h70
  text "TRACE WIDTH" at 6483.42,3920.73 h70
  text "SPACING" at 6968.42,3920.73 h70
  text "IMPEDANCE +/- 10%" at 7303.42,3920.73 h70
  text "REFERENCE LAYER" at 8028.42,3920.73 h70
  text "-" at 7091,3750 h65
  text "LAYER-2 (GND LAYER)" at 7989.83,3744.77 h65
  text "5.66 MILS" at 6582.1,3739.75 h65
  text "50 OHM" at 7466.3,3740 h65
  text "TOP" at 6221,3735 h70
  text "50 OHM" at 7463.76,3555.86 h65
  text "L3" at 6258.46,3555 h60
  text "-" at 7093.46,3555 h65
  text "4.5 MILS" at 6579.56,3550.86 h65
  text "LAYER-2 / LAYER-4" at 7987.29,3546.52 h65
  text "100 OHM" at 7463.76,3380.86 h65
  text "L3" at 6258.46,3380 h60
  text "3.5  MILS" at 6579.56,3375.86 h65
  text "6.7 MILS" at 6992.81,3375 h65
  text "LAYER-2 / LAYER-4" at 7987.29,3371.52 h65
  text "-" at 7088.46,3205 h65
  text "50 OHM" at 7473.76,3205.42 h65
  text "LAYER-4/LAYER-6" at 7997.29,3194.23 h65
  text "L5" at 6258.46,3190 h60
  text "4.0 MILS" at 6579.56,3185 h65
  text "-" at 7082.46,3030 h65
  text "50 OHM" at 7472.46,3025 h65
  text "LAYER-7/LAYER-9" at 8002.29,3024.29 h65
  text "L8" at 6258.46,3020 h60
  text "4.5 MILS" at 6579.56,3015 h65
  text "L8" at 6258.46,2844.61 h60
  text "3.5  MILS" at 6579.56,2840.86 h65
  text "6.7 MILS" at 6992.81,2840.86 h65
  text "100 OHM" at 7467.46,2840.86 h65
  text "LAYER-7/LAYER-9" at 8002.29,2840.93 h65
  text "LAYER-9(GND LAYER)" at 8002.29,2671.48 h65
  text "BOTTOM" at 6181.12,2659.94 h60
  text "5.66 MILS" at 6579.56,2660 h65
  text "-" at 7095,2660 h65
  text "50 OHM" at 7482.46,2660 h65
  text "LAYER-9(GND LAYER)" at 8002.29,2495.01 h65
  text "3.7 MILS" at 6579.56,2483.53 h65
  text "7.3 MILS" at 6992.81,2483.53 h65
  text "100 OHM" at 7472.46,2483.53 h65
  text "BOTTOM" at 6184.12,2483.47 h60
  text "LAYER STACK-UP :" at 4499.78,1187.05 h80
  text "Layer" at 4524.58,878 h60
  text "Name" at 4934.49,878 h60
  text "Material" at 5864.23,878 h60
  text "Thickness" at 6724,878 h60
  text "Constant" at 7373.84,878 h60
  text "Board Layer Stack" at 7943.7,878 h60
  text "Top Overlay" at 4934.49,758 h60
  text "Top Solder" at 4934.49,638 h60
  text "Solder Resist" at 5864.23,638 h60
  text "0.50mil" at 6724,638 h60
  text "3.5" at 7373.84,638 h60
  text "1" at 4524.58,518 h60
  text "Top Layer" at 4934.49,518 h60
  text "1.40mil" at 6724,518 h60
  text "Dielectric 1" at 4934.49,398 h60
  text "FR-4" at 5864.23,398 h60
  text "3.70mil" at 6724,398 h60
  text "4" at 7373.84,398 h60
  text "2" at 4524.58,278 h60
  text "L02_GND1" at 4934.49,278 h60
  text "1.40mil" at 6724,278 h60
  text "Dielectric 2" at 4934.49,158 h60
  text "FR-4" at 5864.23,158 h60
  text "5.00mil" at 6724,158 h60
  text "4" at 7373.84,158 h60
  text "3" at 4524.58,38 h60
  text "L03_SIG1" at 4934.49,38 h60
  text "1.40mil" at 6724,38 h60
  text "Dielectric 3" at 4934.49,-82 h60
  text "FR-4" at 5864.23,-82 h60
  text "7.00mil" at 6724,-82 h60
  text "4" at 7373.84,-82 h60
  text "4" at 4524.58,-202 h60
  text "L04_GND2" at 4934.49,-202 h60
  text "1.40mil" at 6724,-202 h60
  text "Dielectric 4" at 4934.49,-322 h60
  text "FR-4" at 5864.23,-322 h60
  text "4.00mil" at 6724,-322 h60
  text "4" at 7373.84,-322 h60
  text "5" at 4524.58,-442 h60
  text "L05_SIG2" at 4934.49,-442 h60
  text "1.40mil" at 6724,-442 h60
  text "Dielectric 5" at 4934.49,-562 h60
  text "FR-4" at 5864.23,-562 h60
  text "7.00mil" at 6724,-562 h60
  text "4" at 7373.84,-562 h60
  text "6" at 4524.58,-682 h60
  text "L06_PWR" at 4934.49,-682 h60
  text "1.40mil" at 6724,-682 h60
  text "Dielectric 6" at 4934.49,-802 h60
  text "FR-4" at 5864.23,-802 h60
  text "4.00mil" at 6724,-802 h60
  text "4" at 7373.84,-802 h60
  text "7" at 4524.58,-922 h60
  text "L07_GND3" at 4934.49,-922 h60
  text "1.40mil" at 6724,-922 h60
  text "Dielectric 7" at 4934.49,-1042 h60
  text "FR-4" at 5864.23,-1042 h60
  text "7.00mil" at 6724,-1042 h60
  text "4" at 7373.84,-1042 h60
  text "8" at 4524.58,-1162 h60
  text "L08_SIG3" at 4934.49,-1162 h60
  text "1.40mil" at 6724,-1162 h60
  text "Dielectric 8" at 4934.49,-1282 h60
  text "FR-4" at 5864.23,-1282 h60
  text "5.00mil" at 6724,-1282 h60
  text "4" at 7373.84,-1282 h60
  text "9" at 4524.58,-1402 h60
  text "L09_GND4" at 4934.49,-1402 h60
  text "1.40mil" at 6724,-1402 h60
  text "Dielectric 9" at 4934.49,-1522 h60
  text "FR-4" at 5864.23,-1522 h60
  text "3.70mil" at 6724,-1522 h60
  text "4" at 7373.84,-1522 h60
  text "10" at 4524.58,-1642 h60
  text "Bottom Layer" at 4934.49,-1642 h60
  text "1.40mil" at 6724,-1642 h60
  text "Bottom Solder" at 4934.49,-1762 h60
  text "Solder Resist" at 5864.23,-1762 h60
  text "0.50mil" at 6724,-1762 h60
  text "3.5" at 7373.84,-1762 h60
  text "Bottom Overlay" at 4934.49,-1882 h60
  text "Total board thickness:" at 4524.58,-2002 h60
  text "61.40mil" at 6724,-2002 h60
  text ".Layer_Name" at -335.67,-2480.71 h60
Drill Drawing:
  circle w10: c-527.92,5825.38 r22.1
  circle w10: c-527.92,5825.38 r36.84
  circle w10: c-527.92,5328.1 r36.84
  lines w10: -564.75,4830.82 -527.92,4793.99 -491.08,4830.82 -527.92,4867.66 -564.75,4830.82 ; -564.75,4959.75 -491.08,4959.75 -491.08,5033.42 -564.75,5033.42 -564.75,4959.75 ; -564.75,5125.51 -527.92,5143.93 -491.08,5125.51 -509.5,5162.34 -491.08,5199.18 -527.92,5180.76 -564.75,5199.18 -546.34,5162.34 -564.75,5125.51 ; -564.75,5457.03 -491.08,5457.03 -491.08,5530.7 -564.75,5530.7 -564.75,5457.03 ; -564.75,5641.21 -546.34,5641.21 -527.92,5622.79 -509.5,5641.21 -491.08,5641.21 -509.5,5659.62 -491.08,5678.04 -509.5,5678.04 -527.92,5696.46 -546.34,5678.04 -564.75,5678.04 -546.34,5659.62 -564.75,5641.21 ; -550.02,4974.48 -505.82,4974.48 -505.82,5018.68 -550.02,5018.68 -550.02,4974.48
  lines w15: -630.5,4744.26 3575.25,4744.26 ; -630.5,5904.58 3575.25,5904.58 ; -180.02,4578.5 -180.02,6070.34 ; 221.95,4578.5 221.95,6070.34 ; 1008.5,4578.5 1008.5,6070.34 ; 1354.02,4578.5 1354.02,6070.34 ; 1854.23,4578.5 1854.23,6070.34 ; 2820,4578.5 2820,6070.34 ; -630.5,4578.5 3575.25,4578.5 3575.25,6070.34 -630.5,6070.34 -630.5,4578.5
  text "Symbol" at -531.04,5954.31 h96
  text "Count" at -130.29,5954.31 h96
  text "Hole Size" at 271.68,5954.31 h96
  text "Plated" at 1058.22,5954.31 h96
  text "Hole Type" at 1403.75,5954.31 h96
  text "Drill Layer Pair" at 1903.96,5954.31 h96
  text "Hole Tolerance" at 2869.73,5954.31 h96
  text "54" at -130.29,5788.55 h80
  text "7.87mil (0.200mm)" at 271.68,5788.55 h80
  text "PTH" at 1058.22,5788.55 h80
  text "Round" at 1403.75,5788.55 h80
  text "Top Layer - Bottom Layer" at 1903.96,5788.55 h80
  text "+/-3.00mil" at 2869.73,5788.55 h80
  text "777" at -130.29,5622.79 h80
  text "8.00mil (0.203mm)" at 271.68,5622.79 h80
  text "PTH" at 1058.22,5622.79 h80
  text "Round" at 1403.75,5622.79 h80
  text "Top Layer - Bottom Layer" at 1903.96,5622.79 h80
  text "+/-3.00mil" at 2869.73,5622.79 h80
  text "4" at -130.29,5457.03 h80
  text "37.99mil (0.965mm)" at 271.68,5457.03 h80
  text "PTH" at 1058.22,5457.03 h80
  text "Round" at 1403.75,5457.03 h80
  text "Top Layer - Bottom Layer" at 1903.96,5457.03 h80
  text "5" at -130.29,5291.27 h80
  text "37.99mil (0.965mm)" at 271.68,5291.27 h80
  text "PTH" at 1058.22,5291.27 h80
  text "Round" at 1403.75,5291.27 h80
  text "Top Layer - Bottom Layer" at 1903.96,5291.27 h80
  text "+/-3.00mil" at 2869.73,5291.27 h80
  text "5" at -130.29,5125.51 h80
  text "40.00mil (1.016mm)" at 271.68,5125.51 h80
  text "NPTH" at 1058.22,5125.51 h80
  text "Round" at 1403.75,5125.51 h80
  text "Top Layer - Bottom Layer" at 1903.96,5125.51 h80
  text "+/-3.00mil" at 2869.73,5125.51 h80
  text "2" at -130.29,4959.75 h80
  text "40.16mil (1.020mm)" at 271.68,4959.75 h80
  text "NPTH" at 1058.22,4959.75 h80
  text "Round" at 1403.75,4959.75 h80
  text "Top Layer - Bottom Layer" at 1903.96,4959.75 h80
  text "+/-3.00mil" at 2869.73,4959.75 h80
  text "4" at -130.29,4793.99 h80
  text "159.00mil (4.039mm)" at 271.68,4793.99 h80
  text "NPTH" at 1058.22,4793.99 h80
  text "Round" at 1403.75,4793.99 h80
  text "Top Layer - Bottom Layer" at 1903.96,4793.99 h80
  text "+/-3.00mil" at 2869.73,4793.99 h80
  text "851 Total" at -130.29,4628.23 h80
  text ".Layer_Name" at -323.89,-2500.75 h60
M17 Embedded Cavity:
  text ".Layer_Name" at -335.67,-2480.71 h60
M18 Embedded Assembly:
  text ".Layer_Name" at -335.67,-2480.71 h60
M19 Embedded Keepout:
  text ".Layer_Name" at -335.67,-2480.71 h60
Sheet:
  drawing of 56 lines, arcs and shapes, not listed
  text "1" at -161.06,6394.24 h70
  text "2" at 2334.61,6394.24 h70
  text "3" at 4823.95,6394.24 h70
  text "4" at 7330.62,6394.24 h70
  text "5" at 9829.61,6394.24 h70
  text "6" at 12334.61,6394.24 h70
  text "A" at -1317.39,5251.24 h70
  text "A" at 13482.61,5251.24 h70
  text "B" at -1317.39,2871.24 h70
  text "B" at 13482.61,2871.24 h70
  text "C" at -1317.39,496.24 h70
  text "C" at 13482.61,496.24 h70
  text "PROJECT TITLE:" at 10442.61,-1364.76 h45
  text ".PRJ_Title" at 10492.61,-1498.08 h70
  text "DESIGNED FOR:" at 10442.61,-1665.76 h45
  text ".PRJ_Customer" at 10492.61,-1805.76 h70
  text "D" at -1317.39,-1873.76 h70
  text "D" at 13482.61,-1873.76 h70
  text "FILE NAME:" at 10442.61,-1965.76 h45
  text ".PCB_File_Name_No_Path" at 10492.61,-2085.76 h70
  text "Texas Instruments (TI) and/or its licensors do not warrant the accuracy or completeness of this specification" at 5473.11,-2247.6 h45
  text "ENGINEER:" at 10442.61,-2255.76 h45
  text "LAYOUT BY:" at 11947.61,-2255.76 h45
  text "or any information contained therein. TI and/or its licensors do not warrant that this design will meet" at 5428.12,-2360.26 h45
  text ".PRJ_Engineer" at 10492.61,-2410.75 h70
  text ".PCB_Layout" at 11998.11,-2410.75 h70
  text "the specifications, will be suitable for your application or fit for any particular purpose, or will operate in" at 5428.12,-2472.93 h45
  text ".Layer_Name" at -323.89,-2500.75 h60
  text "ALTIUM DESIGNER VERSION:" at 11947.61,-2565.76 h45
  text "an implementation. TI and/or its licensors do not warrant that the design is production worthy. You should" at 5428.12,-2585.59 h45
  text "completely validate and test your design implementation to confirm the system functionality for your application." at 5473.11,-2698.26 h45
  text ".print_Scale" at 10492.61,-2699.08 h70
  text ".Application_BuildNumber" at 11998.11,-2699.08 h70
  text "1" at -161.06,-2905.76 h70
  text "2" at 2334.61,-2905.76 h70
  text "3" at 4823.95,-2905.76 h70
  text "4" at 7330.62,-2905.76 h70
  text "5" at 9829.61,-2905.76 h70
  text "6" at 12334.61,-2905.76 h70

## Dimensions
-410,2121.49 to 2345.9,2121.49 on M2 Board Dimensions
-410,-155 to -410,2121.49 on M2 Board Dimensions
